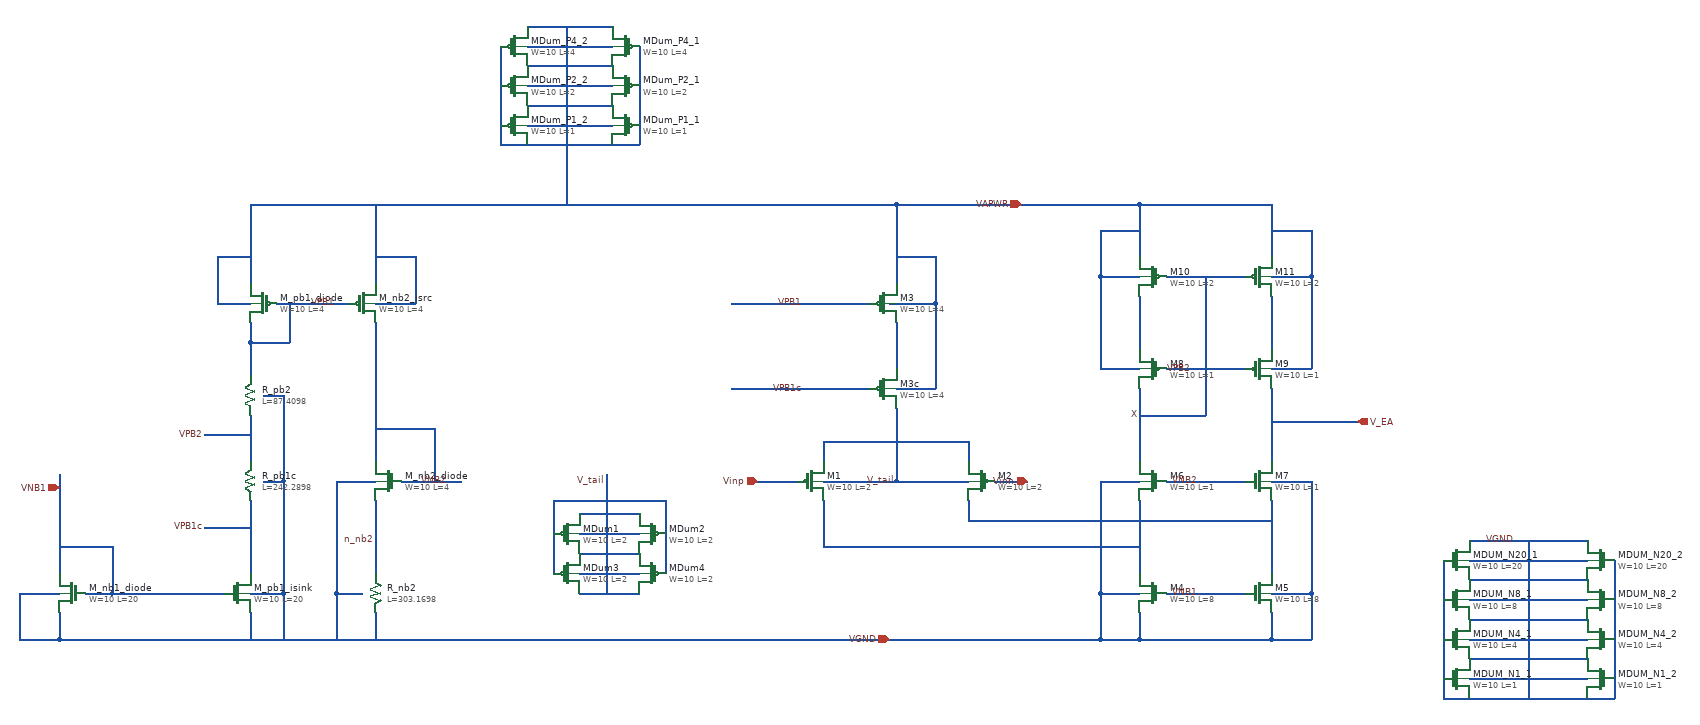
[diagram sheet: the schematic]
v {xschem version=3.4.8RC file_version=1.3}
G {}
K {}
V {}
S {}
F {}
E {}
N -220 -60 -220 -30 {lab=V_tail}
N -220 -60 0 -60 {lab=V_tail}
N 0 -60 0 -30 {lab=V_tail}
N -110 -110 -110 -60 {lab=V_tail}
N -110 -240 -110 -170 {lab=#net1}
N 300 170 420 170 {lab=VNB1}
N 300 0 420 0 {lab=VNB2}
N 260 30 260 140 {lab=#net2}
N 460 30 460 140 {lab=#net3}
N 460 200 460 240 {lab=VGND}
N 260 240 460 240 {lab=VGND}
N 260 200 260 240 {lab=VGND}
N -0 30 0 60 {lab=#net3}
N 0 60 460 60 {lab=#net3}
N -220 30 -220 100 {lab=#net2}
N -220 100 260 100 {lab=#net2}
N 260 -140 260 -30 {lab=X}
N 460 -140 460 -30 {lab=V_EA}
N 300 -170 420 -170 {lab=VPB2}
N 300 -310 420 -310 {lab=X}
N 360 -310 360 -100 {lab=X}
N 260 -100 360 -100 {lab=X}
N 260 -280 260 -200 {lab=#net4}
N 460 -280 460 -200 {lab=#net5}
N 260 -410 260 -340 {lab=VAPWR}
N 260 -420 260 -410 {lab=VAPWR}
N 260 -420 460 -420 {lab=VAPWR}
N 460 -420 460 -340 {lab=VAPWR}
N -110 -420 -110 -300 {lab=VAPWR}
N -110 -420 260 -420 {lab=VAPWR}
N 460 -90 590 -90 {lab=V_EA}
N 460 -310 520 -310 {lab=VAPWR}
N 520 -380 520 -310 {lab=VAPWR}
N 460 -380 520 -380 {lab=VAPWR}
N 200 -310 260 -310 {lab=VAPWR}
N 200 -380 200 -310 {lab=VAPWR}
N 200 -380 260 -380 {lab=VAPWR}
N 200 -170 260 -170 {lab=VAPWR}
N 200 -310 200 -170 {lab=VAPWR}
N 460 -170 520 -170 {lab=VAPWR}
N 520 -310 520 -170 {lab=VAPWR}
N 200 170 260 170 {lab=VGND}
N 200 170 200 240 {lab=VGND}
N 200 240 260 240 {lab=VGND}
N 460 170 520 170 {lab=VGND}
N 520 170 520 240 {lab=VGND}
N 460 240 520 240 {lab=VGND}
N 200 -0 260 -0 {lab=VGND}
N 200 0 200 170 {lab=VGND}
N 460 -0 520 0 {lab=VGND}
N 520 0 520 170 {lab=VGND}
N -220 0 -110 -0 {lab=V_tail}
N -110 -60 -110 -0 {lab=V_tail}
N -110 -0 -0 -0 {lab=V_tail}
N -300 -140 -150 -140 {lab=VPB1c}
N -300 -270 -150 -270 {lab=VPB1}
N -320 0 -260 0 {lab=Vinp}
N 40 -0 90 -0 {lab=Vinn}
N -810 240 -110 240 {lab=VGND}
N -1340 170 -1300 170 {lab=VNB1}
N -1300 100 -1300 170 {lab=VNB1}
N -1380 100 -1300 100 {lab=VNB1}
N -1380 -10 -1380 140 {lab=VNB1}
N -1380 240 -1100 240 {lab=VGND}
N -1380 200 -1380 240 {lab=VGND}
N -1440 170 -1380 170 {lab=VGND}
N -1440 170 -1440 230 {lab=VGND}
N -1440 230 -1440 240 {lab=VGND}
N -1440 240 -1380 240 {lab=VGND}
N -120 -270 -50 -270 {lab=VAPWR}
N -50 -340 -50 -270 {lab=VAPWR}
N -110 -340 -50 -340 {lab=VAPWR}
N -110 -140 -50 -140 {lab=VAPWR}
N -50 -270 -50 -140 {lab=VAPWR}
N -1300 170 -1130 170 {lab=VNB1}
N -1090 200 -1090 240 {lab=VGND}
N -1090 170 -1040 170 {lab=VGND}
N -1040 170 -1040 240 {lab=VGND}
N -1090 60 -1090 140 {lab=VPB1c}
N -1090 -420 -1090 -300 {lab=VAPWR}
N -800 -420 -420 -420 {lab=VAPWR}
N -1140 -270 -1090 -270 {lab=VAPWR}
N -1140 -340 -1140 -270 {lab=VAPWR}
N -1140 -340 -1090 -340 {lab=VAPWR}
N -1100 240 -810 240 {lab=VGND}
N -1090 -420 -800 -420 {lab=VAPWR}
N -1050 -270 -940 -270 {lab=VPB1}
N -1090 -210 -1030 -210 {lab=VPB1}
N -1030 -270 -1030 -210 {lab=VPB1}
N -900 -420 -900 -300 {lab=VAPWR}
N -900 -270 -840 -270 {lab=VAPWR}
N -840 -340 -840 -270 {lab=VAPWR}
N -900 -340 -840 -340 {lab=VAPWR}
N -900 -240 -900 -30 {lab=VNB2}
N -860 0 -770 0 {lab=VNB2}
N -900 -80 -810 -80 {lab=VNB2}
N -810 -80 -810 0 {lab=VNB2}
N -900 200 -900 240 {lab=VGND}
N -960 170 -920 170 {lab=VGND}
N -960 170 -960 240 {lab=VGND}
N -900 30 -900 140 {lab=n_nb2}
N -420 -420 -110 -420 {lab=VAPWR}
N -110 240 200 240 {lab=VGND}
N -960 -0 -900 0 {lab=VGND}
N -960 0 -960 170 {lab=VGND}
N -360 -270 -300 -270 {lab=VPB1}
N -360 -140 -300 -140 {lab=VPB1c}
N -1090 -240 -1090 -210 {lab=VPB1}
N -1040 30 -1040 170 {lab=VGND}
N -1090 30 -1090 60 {lab=VPB1c}
N -1070 0 -1040 -0 {lab=VGND}
N -1040 -0 -1040 30 {lab=VGND}
N -1160 70 -1090 70 {lab=VPB1c}
N -1090 -210 -1090 -160 {lab=VPB1}
N -1090 -100 -1090 -30 {lab=VPB2}
N -1070 -130 -1040 -130 {lab=VGND}
N -1040 -130 -1040 -0 {lab=VGND}
N -1160 -70 -1090 -70 {lab=VPB2}
N -460 80 -460 140 {lab=V_tail}
N -590 170 -500 170 {lab=V_tail}
N -590 140 -500 140 {lab=V_tail}
N -590 110 -500 110 {lab=V_tail}
N -590 80 -500 80 {lab=V_tail}
N -590 50 -500 50 {lab=V_tail}
N -550 140 -550 170 {lab=V_tail}
N -550 110 -550 140 {lab=V_tail}
N -550 80 -550 110 {lab=V_tail}
N -550 50 -550 80 {lab=V_tail}
N -550 -10 -550 50 {lab=V_tail}
N -630 80 -630 140 {lab=V_tail}
N -630 30 -630 80 {lab=V_tail}
N -630 30 -550 30 {lab=V_tail}
N -550 30 -460 30 {lab=V_tail}
N -460 30 -460 80 {lab=V_tail}
N -670 -570 -540 -570 {lab=VAPWR}
N -670 -540 -540 -540 {lab=VAPWR}
N -670 -510 -540 -510 {lab=VAPWR}
N -610 -570 -610 -540 {lab=VAPWR}
N -610 -540 -610 -510 {lab=VAPWR}
N -500 -540 -500 -510 {lab=VAPWR}
N -540 -510 -500 -510 {lab=VAPWR}
N -710 -540 -710 -510 {lab=VAPWR}
N -710 -510 -670 -510 {lab=VAPWR}
N -670 -600 -540 -600 {lab=VAPWR}
N -670 -630 -540 -630 {lab=VAPWR}
N -670 -660 -540 -660 {lab=VAPWR}
N -670 -690 -540 -690 {lab=VAPWR}
N -610 -690 -610 -660 {lab=VAPWR}
N -610 -660 -610 -630 {lab=VAPWR}
N -610 -630 -610 -600 {lab=VAPWR}
N -610 -600 -610 -570 {lab=VAPWR}
N -710 -660 -710 -600 {lab=VAPWR}
N -710 -600 -710 -540 {lab=VAPWR}
N -500 -660 -500 -600 {lab=VAPWR}
N -500 -600 -500 -540 {lab=VAPWR}
N -610 -510 -610 -420 {lab=VAPWR}
N 760 90 940 90 {lab=#net6}
N 760 120 940 120 {lab=#net6}
N 760 150 940 150 {lab=#net6}
N 760 180 940 180 {lab=#net6}
N 760 210 940 210 {lab=#net6}
N 760 240 940 240 {lab=#net6}
N 760 270 940 270 {lab=#net6}
N 760 300 940 300 {lab=#net6}
N 760 330 940 330 {lab=#net6}
N 850 300 850 330 {lab=#net6}
N 850 270 850 300 {lab=#net6}
N 850 240 850 270 {lab=#net6}
N 850 210 850 240 {lab=#net6}
N 850 180 850 210 {lab=#net6}
N 850 150 850 180 {lab=#net6}
N 850 120 850 150 {lab=#net6}
N 850 90 850 120 {lab=#net6}
N 980 120 980 180 {lab=#net6}
N 980 180 980 240 {lab=#net6}
N 980 240 980 300 {lab=#net6}
N 980 300 980 330 {lab=#net6}
N 940 330 980 330 {lab=#net6}
N 720 120 720 180 {lab=#net6}
N 720 180 720 240 {lab=#net6}
N 720 240 720 300 {lab=#net6}
N 720 300 720 330 {lab=#net6}
N 720 330 760 330 {lab=#net6}
C {pfet_g5v0d10v5.sym} -240 0 0 0 {name=M1
W=10
L=2
nf=1
mult=24
ad="expr('int((@nf + 1)/2) * @W / @nf * 0.29')"
pd="expr('2*int((@nf + 1)/2) * (@W / @nf + 0.29)')"
as="expr('int((@nf + 2)/2) * @W / @nf * 0.29')"
ps="expr('2*int((@nf + 2)/2) * (@W / @nf + 0.29)')"
nrd="expr('0.29 / @W ')" nrs="expr('0.29 / @W ')"
sa=0 sb=0 sd=0
model=pfet_g5v0d10v5
spiceprefix=X
}
C {nfet_g5v0d10v5.sym} 280 170 0 1 {name=M4
W=10
L=8
nf=1
mult=2
ad="expr('int((@nf + 1)/2) * @W / @nf * 0.29')"
pd="expr('2*int((@nf + 1)/2) * (@W / @nf + 0.29)')"
as="expr('int((@nf + 2)/2) * @W / @nf * 0.29')"
ps="expr('2*int((@nf + 2)/2) * (@W / @nf + 0.29)')"
nrd="expr('0.29 / @W ')" nrs="expr('0.29 / @W ')"
sa=0 sb=0 sd=0
model=nfet_g5v0d10v5
spiceprefix=X
}
C {pfet_g5v0d10v5.sym} 20 0 0 1 {name=M2
W=10
L=2
nf=1
mult=24
ad="expr('int((@nf + 1)/2) * @W / @nf * 0.29')"
pd="expr('2*int((@nf + 1)/2) * (@W / @nf + 0.29)')"
as="expr('int((@nf + 2)/2) * @W / @nf * 0.29')"
ps="expr('2*int((@nf + 2)/2) * (@W / @nf + 0.29)')"
nrd="expr('0.29 / @W ')" nrs="expr('0.29 / @W ')"
sa=0 sb=0 sd=0
model=pfet_g5v0d10v5
spiceprefix=X
}
C {pfet_g5v0d10v5.sym} -130 -270 0 0 {name=M3
W=10
L=4
nf=1
mult=4
ad="expr('int((@nf + 1)/2) * @W / @nf * 0.29')"
pd="expr('2*int((@nf + 1)/2) * (@W / @nf + 0.29)')"
as="expr('int((@nf + 2)/2) * @W / @nf * 0.29')"
ps="expr('2*int((@nf + 2)/2) * (@W / @nf + 0.29)')"
nrd="expr('0.29 / @W ')" nrs="expr('0.29 / @W ')"
sa=0 sb=0 sd=0
model=pfet_g5v0d10v5
spiceprefix=X
}
C {pfet_g5v0d10v5.sym} -130 -140 0 0 {name=M3c
W=10
L=4
nf=1
mult=4
ad="expr('int((@nf + 1)/2) * @W / @nf * 0.29')"
pd="expr('2*int((@nf + 1)/2) * (@W / @nf + 0.29)')"
as="expr('int((@nf + 2)/2) * @W / @nf * 0.29')"
ps="expr('2*int((@nf + 2)/2) * (@W / @nf + 0.29)')"
nrd="expr('0.29 / @W ')" nrs="expr('0.29 / @W ')"
sa=0 sb=0 sd=0
model=pfet_g5v0d10v5
spiceprefix=X
}
C {nfet_g5v0d10v5.sym} 440 170 0 0 {name=M5
W=10
L=8
nf=1
mult=2
ad="expr('int((@nf + 1)/2) * @W / @nf * 0.29')"
pd="expr('2*int((@nf + 1)/2) * (@W / @nf + 0.29)')"
as="expr('int((@nf + 2)/2) * @W / @nf * 0.29')"
ps="expr('2*int((@nf + 2)/2) * (@W / @nf + 0.29)')"
nrd="expr('0.29 / @W ')" nrs="expr('0.29 / @W ')"
sa=0 sb=0 sd=0
model=nfet_g5v0d10v5
spiceprefix=X
}
C {nfet_g5v0d10v5.sym} 280 0 0 1 {name=M6
W=10
L=1
nf=1
mult=1
ad="expr('int((@nf + 1)/2) * @W / @nf * 0.29')"
pd="expr('2*int((@nf + 1)/2) * (@W / @nf + 0.29)')"
as="expr('int((@nf + 2)/2) * @W / @nf * 0.29')"
ps="expr('2*int((@nf + 2)/2) * (@W / @nf + 0.29)')"
nrd="expr('0.29 / @W ')" nrs="expr('0.29 / @W ')"
sa=0 sb=0 sd=0
model=nfet_g5v0d10v5
spiceprefix=X
}
C {nfet_g5v0d10v5.sym} 440 0 0 0 {name=M7
W=10
L=1
nf=1
mult=1
ad="expr('int((@nf + 1)/2) * @W / @nf * 0.29')"
pd="expr('2*int((@nf + 1)/2) * (@W / @nf + 0.29)')"
as="expr('int((@nf + 2)/2) * @W / @nf * 0.29')"
ps="expr('2*int((@nf + 2)/2) * (@W / @nf + 0.29)')"
nrd="expr('0.29 / @W ')" nrs="expr('0.29 / @W ')"
sa=0 sb=0 sd=0
model=nfet_g5v0d10v5
spiceprefix=X
}
C {pfet_g5v0d10v5.sym} 280 -170 0 1 {name=M8
W=10
L=1
nf=1
mult=4
ad="expr('int((@nf + 1)/2) * @W / @nf * 0.29')"
pd="expr('2*int((@nf + 1)/2) * (@W / @nf + 0.29)')"
as="expr('int((@nf + 2)/2) * @W / @nf * 0.29')"
ps="expr('2*int((@nf + 2)/2) * (@W / @nf + 0.29)')"
nrd="expr('0.29 / @W ')" nrs="expr('0.29 / @W ')"
sa=0 sb=0 sd=0
model=pfet_g5v0d10v5
spiceprefix=X
}
C {pfet_g5v0d10v5.sym} 440 -170 0 0 {name=M9
W=10
L=1
nf=1
mult=4
ad="expr('int((@nf + 1)/2) * @W / @nf * 0.29')"
pd="expr('2*int((@nf + 1)/2) * (@W / @nf + 0.29)')"
as="expr('int((@nf + 2)/2) * @W / @nf * 0.29')"
ps="expr('2*int((@nf + 2)/2) * (@W / @nf + 0.29)')"
nrd="expr('0.29 / @W ')" nrs="expr('0.29 / @W ')"
sa=0 sb=0 sd=0
model=pfet_g5v0d10v5
spiceprefix=X
}
C {pfet_g5v0d10v5.sym} 280 -310 0 1 {name=M10
W=10
L=2
nf=1
mult=4
ad="expr('int((@nf + 1)/2) * @W / @nf * 0.29')"
pd="expr('2*int((@nf + 1)/2) * (@W / @nf + 0.29)')"
as="expr('int((@nf + 2)/2) * @W / @nf * 0.29')"
ps="expr('2*int((@nf + 2)/2) * (@W / @nf + 0.29)')"
nrd="expr('0.29 / @W ')" nrs="expr('0.29 / @W ')"
sa=0 sb=0 sd=0
model=pfet_g5v0d10v5
spiceprefix=X
}
C {pfet_g5v0d10v5.sym} 440 -310 0 0 {name=M11
W=10
L=2
nf=1
mult=4
ad="expr('int((@nf + 1)/2) * @W / @nf * 0.29')"
pd="expr('2*int((@nf + 1)/2) * (@W / @nf + 0.29)')"
as="expr('int((@nf + 2)/2) * @W / @nf * 0.29')"
ps="expr('2*int((@nf + 2)/2) * (@W / @nf + 0.29)')"
nrd="expr('0.29 / @W ')" nrs="expr('0.29 / @W ')"
sa=0 sb=0 sd=0
model=pfet_g5v0d10v5
spiceprefix=X
}
C {lab_pin.sym} 260 -100 2 1 {name=p2 sig_type=std_logic lab=X


}
C {lab_pin.sym} -110 0 1 1 {name=p3 sig_type=std_logic lab=V_tail

}
C {lab_pin.sym} -250 -270 3 1 {name=p6 sig_type=std_logic lab=VPB1


}
C {lab_pin.sym} -250 -140 3 1 {name=p7 sig_type=std_logic lab=VPB1c



}
C {lab_pin.sym} 350 170 3 1 {name=p8 sig_type=std_logic lab=VNB1


}
C {lab_pin.sym} 350 0 3 1 {name=p9 sig_type=std_logic lab=VNB2


}
C {lab_pin.sym} 340 -170 3 1 {name=p10 sig_type=std_logic lab=VPB2


}
C {nfet_g5v0d10v5.sym} -1360 170 0 1 {name=M_nb1_diode
W=10
L=20
nf=1
mult=1
ad="expr('int((@nf + 1)/2) * @W / @nf * 0.29')"
pd="expr('2*int((@nf + 1)/2) * (@W / @nf + 0.29)')"
as="expr('int((@nf + 2)/2) * @W / @nf * 0.29')"
ps="expr('2*int((@nf + 2)/2) * (@W / @nf + 0.29)')"
nrd="expr('0.29 / @W ')" nrs="expr('0.29 / @W ')"
sa=0 sb=0 sd=0
model=nfet_g5v0d10v5
spiceprefix=X
}
C {opin.sym} 590 -90 0 0 {name=p12 lab=V_EA
}
C {iopin.sym} 80 -420 1 0 {name=p21 lab=VAPWR
}
C {ipin.sym} -320 0 0 0 {name=p1 lab=Vinp}
C {ipin.sym} 90 0 2 0 {name=p4 lab=Vinn}
C {ipin.sym} -1380 10 0 0 {name=p5 lab=VNB1
}
C {pfet_g5v0d10v5.sym} -1070 -270 0 1 {name=M_pb1_diode
W=10
L=4
nf=1
mult=1
ad="expr('int((@nf + 1)/2) * @W / @nf * 0.29')"
pd="expr('2*int((@nf + 1)/2) * (@W / @nf + 0.29)')"
as="expr('int((@nf + 2)/2) * @W / @nf * 0.29')"
ps="expr('2*int((@nf + 2)/2) * (@W / @nf + 0.29)')"
nrd="expr('0.29 / @W ')" nrs="expr('0.29 / @W ')"
sa=0 sb=0 sd=0
model=pfet_g5v0d10v5
spiceprefix=X
}
C {nfet_g5v0d10v5.sym} -1110 170 0 0 {name=M_pb1_isink
W=10
L=20
nf=1
mult=1
ad="expr('int((@nf + 1)/2) * @W / @nf * 0.29')"
pd="expr('2*int((@nf + 1)/2) * (@W / @nf + 0.29)')"
as="expr('int((@nf + 2)/2) * @W / @nf * 0.29')"
ps="expr('2*int((@nf + 2)/2) * (@W / @nf + 0.29)')"
nrd="expr('0.29 / @W ')" nrs="expr('0.29 / @W ')"
sa=0 sb=0 sd=0
model=nfet_g5v0d10v5
spiceprefix=X
}
C {lab_pin.sym} -960 -270 3 1 {name=p11 sig_type=std_logic lab=VPB1


}
C {pfet_g5v0d10v5.sym} -920 -270 0 0 {name=M_nb2_isrc
W=10
L=4
nf=1
mult=1
ad="expr('int((@nf + 1)/2) * @W / @nf * 0.29')"
pd="expr('2*int((@nf + 1)/2) * (@W / @nf + 0.29)')"
as="expr('int((@nf + 2)/2) * @W / @nf * 0.29')"
ps="expr('2*int((@nf + 2)/2) * (@W / @nf + 0.29)')"
nrd="expr('0.29 / @W ')" nrs="expr('0.29 / @W ')"
sa=0 sb=0 sd=0
model=pfet_g5v0d10v5
spiceprefix=X
}
C {nfet_g5v0d10v5.sym} -880 0 0 1 {name=M_nb2_diode
W=10
L=4
nf=1
mult=1
ad="expr('int((@nf + 1)/2) * @W / @nf * 0.29')"
pd="expr('2*int((@nf + 1)/2) * (@W / @nf + 0.29)')"
as="expr('int((@nf + 2)/2) * @W / @nf * 0.29')"
ps="expr('2*int((@nf + 2)/2) * (@W / @nf + 0.29)')"
nrd="expr('0.29 / @W ')" nrs="expr('0.29 / @W ')"
sa=0 sb=0 sd=0
model=nfet_g5v0d10v5
spiceprefix=X
}
C {lab_pin.sym} -790 0 3 1 {name=p13 sig_type=std_logic lab=VNB2


}
C {res_high_po_0p69.sym} -900 170 0 0 {name=R_nb2
L=303.1698
model=res_high_po_0p69
spiceprefix=X
mult=1}
C {lab_pin.sym} -900 90 2 1 {name=p17 sig_type=std_logic lab=n_nb2



}
C {res_high_po_0p69.sym} -1090 0 0 1 {name=R_pb1c
L=242.2898
model=res_high_po_0p69
spiceprefix=X
mult=1}
C {iopin.sym} -120 240 1 0 {name=p14 lab=VGND
}
C {lab_pin.sym} -1160 70 0 0 {name=p15 sig_type=std_logic lab=VPB1c



}
C {res_high_po_0p69.sym} -1090 -130 0 1 {name=R_pb2
L=87.4098
model=res_high_po_0p69
spiceprefix=X
mult=1}
C {lab_pin.sym} -1160 -70 0 0 {name=p16 sig_type=std_logic lab=VPB2



}
C {pfet_g5v0d10v5.sym} -610 80 0 0 {name=MDum1
W=10
L=2
nf=1
mult=1
ad="expr('int((@nf + 1)/2) * @W / @nf * 0.29')"
pd="expr('2*int((@nf + 1)/2) * (@W / @nf + 0.29)')"
as="expr('int((@nf + 2)/2) * @W / @nf * 0.29')"
ps="expr('2*int((@nf + 2)/2) * (@W / @nf + 0.29)')"
nrd="expr('0.29 / @W ')" nrs="expr('0.29 / @W ')"
sa=0 sb=0 sd=0
model=pfet_g5v0d10v5
spiceprefix=X
}
C {pfet_g5v0d10v5.sym} -480 80 0 1 {name=MDum2
W=10
L=2
nf=1
mult=1
ad="expr('int((@nf + 1)/2) * @W / @nf * 0.29')"
pd="expr('2*int((@nf + 1)/2) * (@W / @nf + 0.29)')"
as="expr('int((@nf + 2)/2) * @W / @nf * 0.29')"
ps="expr('2*int((@nf + 2)/2) * (@W / @nf + 0.29)')"
nrd="expr('0.29 / @W ')" nrs="expr('0.29 / @W ')"
sa=0 sb=0 sd=0
model=pfet_g5v0d10v5
spiceprefix=X
}
C {pfet_g5v0d10v5.sym} -610 140 0 0 {name=MDum3
W=10
L=2
nf=1
mult=1
ad="expr('int((@nf + 1)/2) * @W / @nf * 0.29')"
pd="expr('2*int((@nf + 1)/2) * (@W / @nf + 0.29)')"
as="expr('int((@nf + 2)/2) * @W / @nf * 0.29')"
ps="expr('2*int((@nf + 2)/2) * (@W / @nf + 0.29)')"
nrd="expr('0.29 / @W ')" nrs="expr('0.29 / @W ')"
sa=0 sb=0 sd=0
model=pfet_g5v0d10v5
spiceprefix=X
}
C {pfet_g5v0d10v5.sym} -480 140 0 1 {name=MDum4
W=10
L=2
nf=1
mult=1
ad="expr('int((@nf + 1)/2) * @W / @nf * 0.29')"
pd="expr('2*int((@nf + 1)/2) * (@W / @nf + 0.29)')"
as="expr('int((@nf + 2)/2) * @W / @nf * 0.29')"
ps="expr('2*int((@nf + 2)/2) * (@W / @nf + 0.29)')"
nrd="expr('0.29 / @W ')" nrs="expr('0.29 / @W ')"
sa=0 sb=0 sd=0
model=pfet_g5v0d10v5
spiceprefix=X
}
C {lab_pin.sym} -550 0 2 1 {name=p18 sig_type=std_logic lab=V_tail

}
C {pfet_g5v0d10v5.sym} -520 -660 0 1 {name=MDum_P4_1
W=10
L=4
nf=1
mult=1
ad="expr('int((@nf + 1)/2) * @W / @nf * 0.29')"
pd="expr('2*int((@nf + 1)/2) * (@W / @nf + 0.29)')"
as="expr('int((@nf + 2)/2) * @W / @nf * 0.29')"
ps="expr('2*int((@nf + 2)/2) * (@W / @nf + 0.29)')"
nrd="expr('0.29 / @W ')" nrs="expr('0.29 / @W ')"
sa=0 sb=0 sd=0
model=pfet_g5v0d10v5
spiceprefix=X
}
C {pfet_g5v0d10v5.sym} -690 -660 0 0 {name=MDum_P4_2
W=10
L=4
nf=1
mult=1
ad="expr('int((@nf + 1)/2) * @W / @nf * 0.29')"
pd="expr('2*int((@nf + 1)/2) * (@W / @nf + 0.29)')"
as="expr('int((@nf + 2)/2) * @W / @nf * 0.29')"
ps="expr('2*int((@nf + 2)/2) * (@W / @nf + 0.29)')"
nrd="expr('0.29 / @W ')" nrs="expr('0.29 / @W ')"
sa=0 sb=0 sd=0
model=pfet_g5v0d10v5
spiceprefix=X
}
C {pfet_g5v0d10v5.sym} -520 -600 0 1 {name=MDum_P2_1
W=10
L=2
nf=1
mult=1
ad="expr('int((@nf + 1)/2) * @W / @nf * 0.29')"
pd="expr('2*int((@nf + 1)/2) * (@W / @nf + 0.29)')"
as="expr('int((@nf + 2)/2) * @W / @nf * 0.29')"
ps="expr('2*int((@nf + 2)/2) * (@W / @nf + 0.29)')"
nrd="expr('0.29 / @W ')" nrs="expr('0.29 / @W ')"
sa=0 sb=0 sd=0
model=pfet_g5v0d10v5
spiceprefix=X
}
C {pfet_g5v0d10v5.sym} -690 -600 0 0 {name=MDum_P2_2
W=10
L=2
nf=1
mult=1
ad="expr('int((@nf + 1)/2) * @W / @nf * 0.29')"
pd="expr('2*int((@nf + 1)/2) * (@W / @nf + 0.29)')"
as="expr('int((@nf + 2)/2) * @W / @nf * 0.29')"
ps="expr('2*int((@nf + 2)/2) * (@W / @nf + 0.29)')"
nrd="expr('0.29 / @W ')" nrs="expr('0.29 / @W ')"
sa=0 sb=0 sd=0
model=pfet_g5v0d10v5
spiceprefix=X
}
C {pfet_g5v0d10v5.sym} -520 -540 0 1 {name=MDum_P1_1
W=10
L=1
nf=1
mult=1
ad="expr('int((@nf + 1)/2) * @W / @nf * 0.29')"
pd="expr('2*int((@nf + 1)/2) * (@W / @nf + 0.29)')"
as="expr('int((@nf + 2)/2) * @W / @nf * 0.29')"
ps="expr('2*int((@nf + 2)/2) * (@W / @nf + 0.29)')"
nrd="expr('0.29 / @W ')" nrs="expr('0.29 / @W ')"
sa=0 sb=0 sd=0
model=pfet_g5v0d10v5
spiceprefix=X
}
C {pfet_g5v0d10v5.sym} -690 -540 0 0 {name=MDum_P1_2
W=10
L=1
nf=1
mult=1
ad="expr('int((@nf + 1)/2) * @W / @nf * 0.29')"
pd="expr('2*int((@nf + 1)/2) * (@W / @nf + 0.29)')"
as="expr('int((@nf + 2)/2) * @W / @nf * 0.29')"
ps="expr('2*int((@nf + 2)/2) * (@W / @nf + 0.29)')"
nrd="expr('0.29 / @W ')" nrs="expr('0.29 / @W ')"
sa=0 sb=0 sd=0
model=pfet_g5v0d10v5
spiceprefix=X
}
C {nfet_g5v0d10v5.sym} 740 180 0 0 {name=MDUM_N8_1
W=10
L=8
nf=1
mult=1
ad="expr('int((@nf + 1)/2) * @W / @nf * 0.29')"
pd="expr('2*int((@nf + 1)/2) * (@W / @nf + 0.29)')"
as="expr('int((@nf + 2)/2) * @W / @nf * 0.29')"
ps="expr('2*int((@nf + 2)/2) * (@W / @nf + 0.29)')"
nrd="expr('0.29 / @W ')" nrs="expr('0.29 / @W ')"
sa=0 sb=0 sd=0
model=nfet_g5v0d10v5
spiceprefix=X
}
C {nfet_g5v0d10v5.sym} 960 180 0 1 {name=MDUM_N8_2
W=10
L=8
nf=1
mult=1
ad="expr('int((@nf + 1)/2) * @W / @nf * 0.29')"
pd="expr('2*int((@nf + 1)/2) * (@W / @nf + 0.29)')"
as="expr('int((@nf + 2)/2) * @W / @nf * 0.29')"
ps="expr('2*int((@nf + 2)/2) * (@W / @nf + 0.29)')"
nrd="expr('0.29 / @W ')" nrs="expr('0.29 / @W ')"
sa=0 sb=0 sd=0
model=nfet_g5v0d10v5
spiceprefix=X
}
C {nfet_g5v0d10v5.sym} 740 240 0 0 {name=MDUM_N4_1
W=10
L=4
nf=1
mult=1
ad="expr('int((@nf + 1)/2) * @W / @nf * 0.29')"
pd="expr('2*int((@nf + 1)/2) * (@W / @nf + 0.29)')"
as="expr('int((@nf + 2)/2) * @W / @nf * 0.29')"
ps="expr('2*int((@nf + 2)/2) * (@W / @nf + 0.29)')"
nrd="expr('0.29 / @W ')" nrs="expr('0.29 / @W ')"
sa=0 sb=0 sd=0
model=nfet_g5v0d10v5
spiceprefix=X
}
C {nfet_g5v0d10v5.sym} 960 240 0 1 {name=MDUM_N4_2
W=10
L=4
nf=1
mult=1
ad="expr('int((@nf + 1)/2) * @W / @nf * 0.29')"
pd="expr('2*int((@nf + 1)/2) * (@W / @nf + 0.29)')"
as="expr('int((@nf + 2)/2) * @W / @nf * 0.29')"
ps="expr('2*int((@nf + 2)/2) * (@W / @nf + 0.29)')"
nrd="expr('0.29 / @W ')" nrs="expr('0.29 / @W ')"
sa=0 sb=0 sd=0
model=nfet_g5v0d10v5
spiceprefix=X
}
C {nfet_g5v0d10v5.sym} 740 300 0 0 {name=MDUM_N1_1
W=10
L=1
nf=1
mult=1
ad="expr('int((@nf + 1)/2) * @W / @nf * 0.29')"
pd="expr('2*int((@nf + 1)/2) * (@W / @nf + 0.29)')"
as="expr('int((@nf + 2)/2) * @W / @nf * 0.29')"
ps="expr('2*int((@nf + 2)/2) * (@W / @nf + 0.29)')"
nrd="expr('0.29 / @W ')" nrs="expr('0.29 / @W ')"
sa=0 sb=0 sd=0
model=nfet_g5v0d10v5
spiceprefix=X
}
C {nfet_g5v0d10v5.sym} 960 300 0 1 {name=MDUM_N1_2
W=10
L=1
nf=1
mult=1
ad="expr('int((@nf + 1)/2) * @W / @nf * 0.29')"
pd="expr('2*int((@nf + 1)/2) * (@W / @nf + 0.29)')"
as="expr('int((@nf + 2)/2) * @W / @nf * 0.29')"
ps="expr('2*int((@nf + 2)/2) * (@W / @nf + 0.29)')"
nrd="expr('0.29 / @W ')" nrs="expr('0.29 / @W ')"
sa=0 sb=0 sd=0
model=nfet_g5v0d10v5
spiceprefix=X
}
C {nfet_g5v0d10v5.sym} 740 120 0 0 {name=MDUM_N20_1
W=10
L=20
nf=1
mult=1
ad="expr('int((@nf + 1)/2) * @W / @nf * 0.29')"
pd="expr('2*int((@nf + 1)/2) * (@W / @nf + 0.29)')"
as="expr('int((@nf + 2)/2) * @W / @nf * 0.29')"
ps="expr('2*int((@nf + 2)/2) * (@W / @nf + 0.29)')"
nrd="expr('0.29 / @W ')" nrs="expr('0.29 / @W ')"
sa=0 sb=0 sd=0
model=nfet_g5v0d10v5
spiceprefix=X
}
C {nfet_g5v0d10v5.sym} 960 120 0 1 {name=MDUM_N20_2
W=10
L=20
nf=1
mult=1
ad="expr('int((@nf + 1)/2) * @W / @nf * 0.29')"
pd="expr('2*int((@nf + 1)/2) * (@W / @nf + 0.29)')"
as="expr('int((@nf + 2)/2) * @W / @nf * 0.29')"
ps="expr('2*int((@nf + 2)/2) * (@W / @nf + 0.29)')"
nrd="expr('0.29 / @W ')" nrs="expr('0.29 / @W ')"
sa=0 sb=0 sd=0
model=nfet_g5v0d10v5
spiceprefix=X
}
C {lab_pin.sym} 830 90 3 1 {name=p19 sig_type=std_logic lab=VGND


}
